VERSION 5.8 ;
BUSBITCHARS "[]" ;
DIVIDERCHAR "/" ;
UNITS
  DATABASE MICRONS 1000 ;
END UNITS
MANUFACTURINGGRID 0.005 ;

SITE core
  CLASS CORE ;
  SIZE 0.2 BY 1.2 ;
END core

LAYER M1
  TYPE ROUTING ;
  DIRECTION HORIZONTAL ;
  PITCH 0.2 ;
  WIDTH 0.07 ;
  SPACING 0.07 ;
END M1

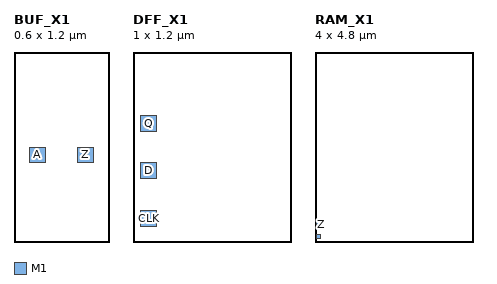
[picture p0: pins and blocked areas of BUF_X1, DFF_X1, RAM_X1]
MACRO BUF_X1
  CLASS CORE ;
  ORIGIN 0 0 ;
  SIZE 0.6 BY 1.2 ;
  SITE core ;
  PIN A
    DIRECTION INPUT ;
    USE SIGNAL ;
    PORT
      LAYER M1 ;
        RECT 0.1 0.5 0.2 0.6 ;
    END
  END A
  PIN Z
    DIRECTION OUTPUT ;
    USE SIGNAL ;
    PORT
      LAYER M1 ;
        RECT 0.4 0.5 0.5 0.6 ;
    END
  END Z
END BUF_X1

MACRO DFF_X1
  CLASS CORE ;
  ORIGIN 0 0 ;
  SIZE 1.0 BY 1.2 ;
  SITE core ;
  PIN CLK
    DIRECTION INPUT ;
    USE SIGNAL ;
    PORT
      LAYER M1 ;
        RECT 0.05 0.10 0.15 0.20 ;
    END
  END CLK
  PIN D
    DIRECTION INPUT ;
    USE SIGNAL ;
    PORT
      LAYER M1 ;
        RECT 0.05 0.40 0.15 0.50 ;
    END
  END D
  PIN Q
    DIRECTION OUTPUT ;
    USE SIGNAL ;
    PORT
      LAYER M1 ;
        RECT 0.05 0.70 0.15 0.80 ;
    END
  END Q
END DFF_X1

MACRO RAM_X1
  CLASS BLOCK ;
  ORIGIN 0 0 ;
  SIZE 4.0 BY 4.8 ;
  PIN A
    DIRECTION INPUT ;
    USE SIGNAL ;
    PORT
      LAYER M1 ;
        RECT 0.05 0.10 0.15 0.20 ;
    END
  END A
  PIN Z
    DIRECTION OUTPUT ;
    USE SIGNAL ;
    PORT
      LAYER M1 ;
        RECT 0.05 0.40 0.15 0.50 ;
    END
  END Z
END RAM_X1

END LIBRARY
